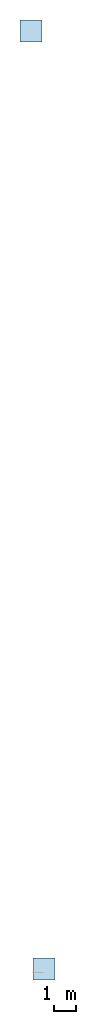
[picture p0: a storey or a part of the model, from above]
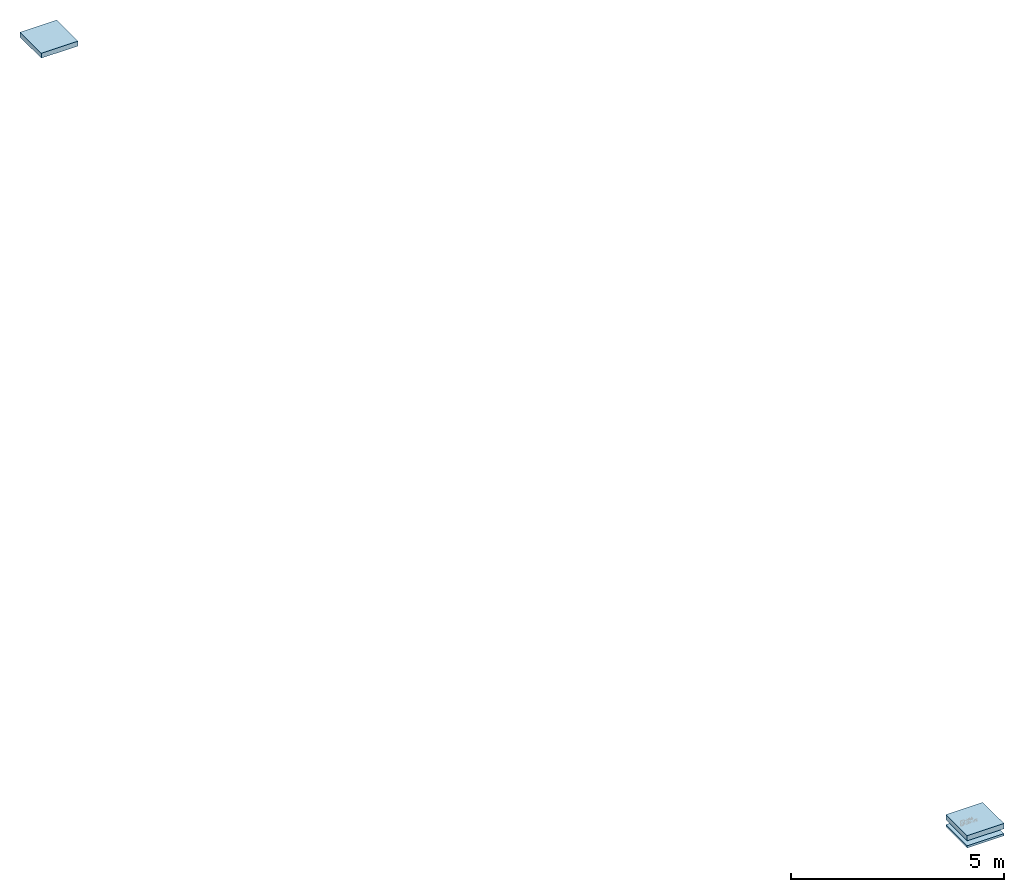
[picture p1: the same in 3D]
Properties of the parts of a building model (IFC4)

# File
Description: ViewDefinition [ReferenceView_V1.2], RevitIdentifiers [VersionGUID: 578dc951-38f8-42b4-9d55-27c226baf1a5, NumberOfSaves: 2], CoordinateReference [CoordinateBase: Gemeinsam genutzte Koordinaten], ExchangeRequirement [Architecture]
File name: 2018_01
Time: 2023-07-05T09:30:04+01:00
Written by: ODA SDAI 23.12
Made in: Autodesk Revit 24.0.5.432 (DEU) - IFC 24.0.5.432

# IfcProject, 2018_01
Phase: Projekt Status

# IfcSite, Default
RefLatitude: 48, 8, 15, 359802; RefLongitude: 11, 34, 47, 783432; RefElevation: 0 m
Pset_SiteCommon - Reference: Projektinformationen

# IfcBuildingElementProxy: Modelltext:075mm Arial, Modelltext:075mm Arial:2510374
In: Default
Type - Pset_BuildingElementProxyCommon - IsExternal: no
Pset_BuildingElementProxyCommon - Reference: 075mm Arial
Pset_EnvironmentalImpactIndicators - Reference: 075mm Arial
Qto_BuildingElementProxyQuantities - NetSurfaceArea: 0.153574 m2; NetVolume: 0.000500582 m3

# IfcElementAssembly: Dächer Baugruppe:fbimSg_Roof_bc_WOD_vis_at_NTR_natuREbuilt_FD-HM-GRÜN-VS_GK3_72cm, Dächer Baugruppe:fbimSg_Roof_bc_WOD_vis_at_NTR_natuREbuilt_FD-HM-GRÜN-VS_GK3_72cm:2510402
In: Default
PredefinedType: USERDEFINED
Pset_ElementAssemblyCommon - Reference: fbimSg_Roof_bc_WOD_vis_at_NTR_natuREbuilt_FD-HM-GRÜN-VS_GK3_72cm; sets with these values: 2

# IfcRoof: Basisdach:fbimSg_Roof_dp_DRW_vis_at_NTR_natuREbuilt_DMh_GK3_u_1,25cm, Basisdach:fbimSg_Roof_dp_DRW_vis_at_NTR_natuREbuilt_DMh_GK3_u_1,25cm:2510395
In: Default
Type - Pset_RoofCommon - IsExternal: yes
Material: fbim_14100505_AT_Schafwolle, fbim_16101505_AT_Gipsfaserplatte
Pset_EnvironmentalImpactIndicators - Reference: fbimSg_Roof_dp_DRW_vis_at_NTR_natuREbuilt_DMh_GK3_u_1,25cm
Pset_RoofCommon - Reference: fbimSg_Roof_dp_DRW_vis_at_NTR_natuREbuilt_DMh_GK3_u_1,25cm
Qto_RoofBaseQuantities - GrossArea: 1 m2; ProjectedArea: 1 m2

# IfcRoof: Basisdach:fbimSg_Roof_dp_INH_vis_at_NTR_natuREbuilt_DMh_GK3_o_35cm, Basisdach:fbimSg_Roof_dp_INH_vis_at_NTR_natuREbuilt_DMh_GK3_o_35cm:2510386
In: Default
Type - Pset_RoofCommon - IsExternal: yes
Material: fbim_20252030_AT_Begruenung_extensiv, fbim_10200515_AT_001_Schutzvlies, fbim_14052005_AT_EPDM_Abdichtungsbahn (2), OENORM A6240 Dämmstoff (Hart)
Pset_EnvironmentalImpactIndicators - Reference: fbimSg_Roof_dp_INH_vis_at_NTR_natuREbuilt_DMh_GK3_o_35cm
Pset_RoofCommon - Reference: fbimSg_Roof_dp_INH_vis_at_NTR_natuREbuilt_DMh_GK3_o_35cm
Qto_RoofBaseQuantities - GrossArea: 1 m2; ProjectedArea: 1 m2

# IfcRoof: Basisdach:fbimSg_Roof_sb_WOD_vis_at_NTR_natuREbuilt_DMh_GK3_k_20cm, Basisdach:fbimSg_Roof_sb_WOD_vis_at_NTR_natuREbuilt_DMh_GK3_k_20cm:2510377
In: Default
Pset_EnvironmentalImpactIndicators - Reference: fbimSg_Roof_sb_WOD_vis_at_NTR_natuREbuilt_DMh_GK3_k_20cm
Pset_RoofCommon - Reference: fbimSg_Roof_sb_WOD_vis_at_NTR_natuREbuilt_DMh_GK3_k_20cm; IsExternal: yes
Qto_RoofBaseQuantities - ProjectedArea: 1 m2

# IfcSlab: Basisdach:fbimSg_Roof_sb_WOD_vis_at_NTR_natuREbuilt_DMh_GK3_k_20cm, Basisdach:fbimSg_Roof_sb_WOD_vis_at_NTR_natuREbuilt_DMh_GK3_k_20cm:2510377
In: Default
Type - PredefinedType: ROOF
Type - Pset_SlabCommon - IsExternal: yes
Material: fbim_AT_KLH_Massivholz
Pset_EnvironmentalImpactIndicators - Reference: fbimSg_Roof_sb_WOD_vis_at_NTR_natuREbuilt_DMh_GK3_k_20cm; sets with these values: 2
Pset_SlabCommon - Reference: fbimSg_Roof_sb_WOD_vis_at_NTR_natuREbuilt_DMh_GK3_k_20cm; PitchAngle: 0 deg
Qto_SlabBaseQuantities - Length: 0.14 m; Perimeter: 4 m; GrossArea: 0.092903 m2; GrossVolume: 0.0130064 m3; NetVolume: 0.14 m3
